VERSION 5.7 ;
  NOWIREEXTENSIONATPIN ON ;
  DIVIDERCHAR "/" ;
  BUSBITCHARS "[]" ;
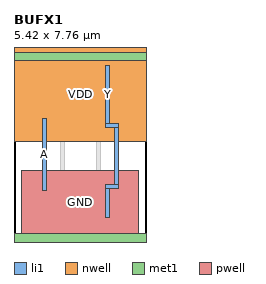
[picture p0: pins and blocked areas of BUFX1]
MACRO BUFX1
  CLASS CORE ;
  FOREIGN BUFX1 ;
  ORIGIN 0.000 0.000 ;
  SIZE 5.420 BY 7.760 ;
  SYMMETRY X Y ;
  SITE unitrh ;
  PIN Y
    DIRECTION OUTPUT ;
    USE SIGNAL ;
    ANTENNADIFFAREA 0.771900 ;
    PORT
      LAYER li1 ;
        RECT 3.740 4.845 3.910 7.200 ;
        RECT 3.740 4.675 4.275 4.845 ;
        RECT 4.105 2.345 4.275 4.675 ;
        RECT 3.735 2.175 4.275 2.345 ;
        RECT 3.735 1.020 3.905 2.175 ;
    END
  END Y
  PIN A
    DIRECTION INPUT ;
    USE SIGNAL ;
    ANTENNAGATEAREA 1.027250 ;
    PORT
      LAYER li1 ;
        RECT 1.145 2.100 1.315 5.045 ;
    END
  END A
  PIN VDD
    DIRECTION INOUT ;
    USE POWER ;
    SHAPE ABUTMENT ;
    PORT
      LAYER nwell ;
        RECT 0.000 4.110 5.420 7.940 ;
      LAYER met1 ;
        RECT 0.000 7.410 5.420 7.760 ;
    END
  END VDD
  PIN GND
    DIRECTION INOUT ;
    USE GROUND ;
    SHAPE ABUTMENT ;
    PORT
      LAYER pwell ;
        RECT 0.320 0.350 5.100 2.900 ;
        RECT 0.000 0.000 5.420 0.350 ;
      LAYER met1 ;
        RECT 0.000 0.000 5.420 0.350 ;
    END
  END GND
  OBS
      LAYER li1 ;
        RECT 0.000 7.410 5.420 7.760 ;
        RECT 0.320 4.290 0.660 7.410 ;
        RECT 1.080 5.365 1.250 7.410 ;
        RECT 1.520 4.845 1.690 7.200 ;
        RECT 1.960 5.365 2.130 7.410 ;
        RECT 1.520 4.675 2.055 4.845 ;
        RECT 0.320 0.350 0.660 2.900 ;
        RECT 1.885 2.345 2.055 4.675 ;
        RECT 2.540 4.290 2.880 7.410 ;
        RECT 3.300 5.365 3.470 7.410 ;
        RECT 4.180 5.365 4.350 7.410 ;
        RECT 1.515 2.175 2.055 2.345 ;
        RECT 1.035 0.800 1.205 1.930 ;
        RECT 1.515 1.020 1.685 2.175 ;
        RECT 2.005 0.800 2.175 1.930 ;
        RECT 1.035 0.630 2.175 0.800 ;
        RECT 1.035 0.350 1.205 0.630 ;
        RECT 1.520 0.350 1.690 0.630 ;
        RECT 2.005 0.350 2.175 0.630 ;
        RECT 2.540 0.350 2.880 2.900 ;
        RECT 3.365 2.100 3.535 5.045 ;
        RECT 4.760 4.290 5.100 7.410 ;
        RECT 3.255 0.800 3.425 1.930 ;
        RECT 4.225 0.800 4.395 1.930 ;
        RECT 3.255 0.630 4.395 0.800 ;
        RECT 3.255 0.350 3.425 0.630 ;
        RECT 3.740 0.350 3.910 0.630 ;
        RECT 4.225 0.350 4.395 0.630 ;
        RECT 4.760 0.350 5.100 2.900 ;
        RECT 0.000 0.000 5.420 0.350 ;
      LAYER mcon ;
        RECT 0.775 7.495 0.945 7.665 ;
        RECT 1.145 7.495 1.315 7.665 ;
        RECT 1.515 7.495 1.685 7.665 ;
        RECT 1.885 7.495 2.055 7.665 ;
        RECT 2.255 7.495 2.425 7.665 ;
        RECT 2.995 7.495 3.165 7.665 ;
        RECT 3.365 7.495 3.535 7.665 ;
        RECT 3.735 7.495 3.905 7.665 ;
        RECT 4.105 7.495 4.275 7.665 ;
        RECT 4.475 7.495 4.645 7.665 ;
        RECT 1.885 2.685 2.055 2.855 ;
        RECT 3.365 2.685 3.535 2.855 ;
        RECT 0.775 0.095 0.945 0.265 ;
        RECT 1.145 0.095 1.315 0.265 ;
        RECT 1.515 0.095 1.685 0.265 ;
        RECT 1.885 0.095 2.055 0.265 ;
        RECT 2.255 0.095 2.425 0.265 ;
        RECT 2.995 0.095 3.165 0.265 ;
        RECT 3.365 0.095 3.535 0.265 ;
        RECT 3.735 0.095 3.905 0.265 ;
        RECT 4.105 0.095 4.275 0.265 ;
        RECT 4.475 0.095 4.645 0.265 ;
      LAYER met1 ;
        RECT 1.855 2.855 2.085 2.885 ;
        RECT 3.335 2.855 3.565 2.885 ;
        RECT 1.825 2.685 3.595 2.855 ;
        RECT 1.855 2.655 2.085 2.685 ;
        RECT 3.335 2.655 3.565 2.685 ;
  END
END BUFX1
END LIBRARY

